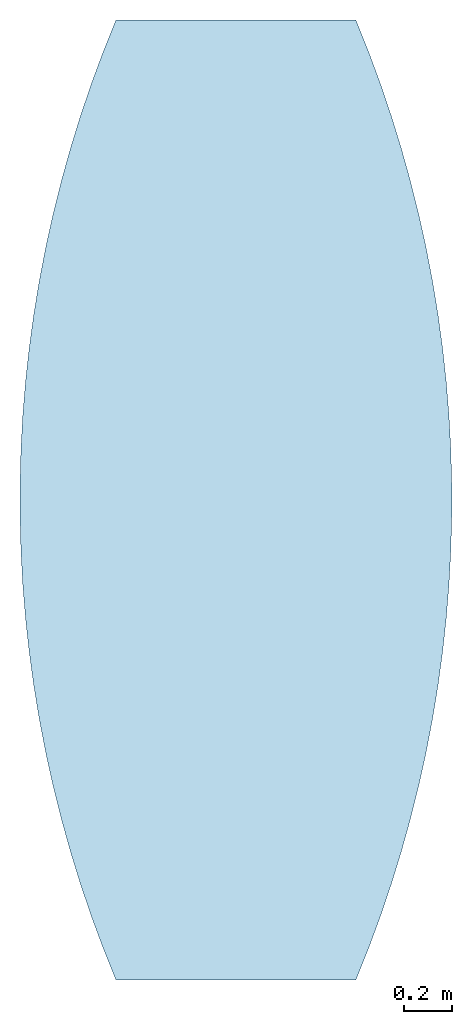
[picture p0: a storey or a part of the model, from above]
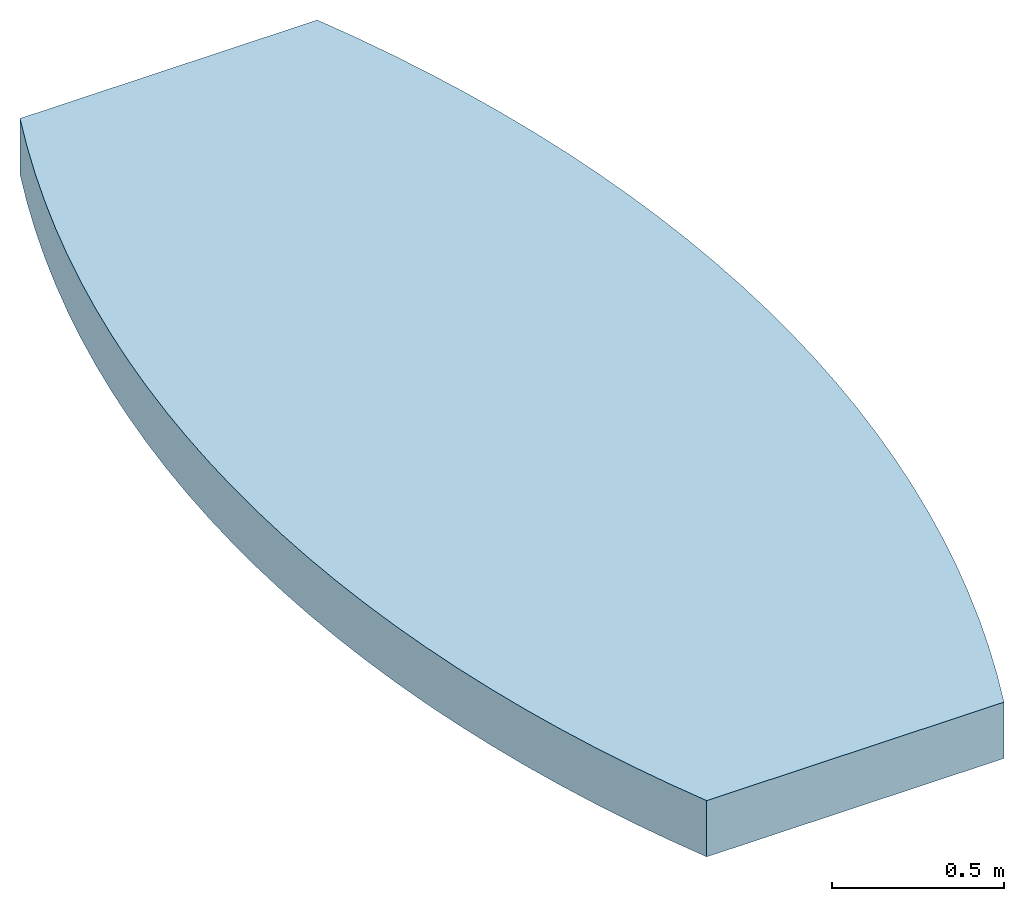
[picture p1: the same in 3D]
Properties of the parts of a building model (IFC4)

# File
Description: ViewDefinition [notYetAssigned]
Time: 2014-12-07T23:39:47
Author: Jon
Organization: Unknown
Written by: ggIFC - Exporter by Geometry Gym Pty Ltd
Made in: ggIFC - Exporter by Geometry Gym Pty Ltd
Comment: name
Comment: time_stamp
Comment: author
Comment: organization
Comment: preprocessor_version
Comment: originating_system
Comment: authorization

# IfcProject, IfcProject
LongName: IfcProject

# IfcSlabStandardCase: 200mm Concrete
In: IfcBuilding
Type - PredefinedType: FLOOR; Material: Concrete 200 mm
